VERSION 5.8 ;
BUSBITCHARS "[]" ;
DIVIDERCHAR "/" ;
UNITS
    DATABASE MICRONS 1000 ;
END UNITS

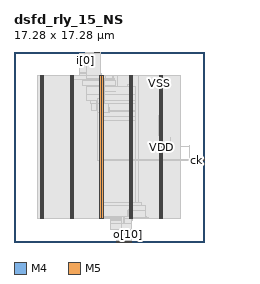
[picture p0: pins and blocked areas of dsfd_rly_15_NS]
MACRO dsfd_rly_15_NS
  FOREIGN dsfd_rly_15_NS 0 0 ;
  CLASS BLOCK ;
  SIZE 17.28 BY 17.28 ;
  PIN ck
    DIRECTION INPUT ;
    USE SIGNAL ;
    PORT
      LAYER M4 ;
        RECT  17.196 7.44 17.28 7.464 ;
    END
  END ck
  PIN i[0]
    DIRECTION INPUT ;
    USE SIGNAL ;
    PORT
      LAYER M5 ;
        RECT  6.48 17.196 6.504 17.28 ;
    END
  END i[0]
  PIN i[10]
    DIRECTION INPUT ;
    USE SIGNAL ;
    PORT
      LAYER M5 ;
        RECT  7.44 17.196 7.464 17.28 ;
    END
  END i[10]
  PIN i[11]
    DIRECTION INPUT ;
    USE SIGNAL ;
    PORT
      LAYER M5 ;
        RECT  7.536 17.196 7.56 17.28 ;
    END
  END i[11]
  PIN i[12]
    DIRECTION INPUT ;
    USE SIGNAL ;
    PORT
      LAYER M5 ;
        RECT  7.632 17.196 7.656 17.28 ;
    END
  END i[12]
  PIN i[13]
    DIRECTION INPUT ;
    USE SIGNAL ;
    PORT
      LAYER M5 ;
        RECT  7.728 17.196 7.752 17.28 ;
    END
  END i[13]
  PIN i[14]
    DIRECTION INPUT ;
    USE SIGNAL ;
    PORT
      LAYER M5 ;
        RECT  7.824 17.196 7.848 17.28 ;
    END
  END i[14]
  PIN i[1]
    DIRECTION INPUT ;
    USE SIGNAL ;
    PORT
      LAYER M5 ;
        RECT  6.576 17.196 6.6 17.28 ;
    END
  END i[1]
  PIN i[2]
    DIRECTION INPUT ;
    USE SIGNAL ;
    PORT
      LAYER M5 ;
        RECT  6.672 17.196 6.696 17.28 ;
    END
  END i[2]
  PIN i[3]
    DIRECTION INPUT ;
    USE SIGNAL ;
    PORT
      LAYER M5 ;
        RECT  6.768 17.196 6.792 17.28 ;
    END
  END i[3]
  PIN i[4]
    DIRECTION INPUT ;
    USE SIGNAL ;
    PORT
      LAYER M5 ;
        RECT  6.864 17.196 6.888 17.28 ;
    END
  END i[4]
  PIN i[5]
    DIRECTION INPUT ;
    USE SIGNAL ;
    PORT
      LAYER M5 ;
        RECT  6.96 17.196 6.984 17.28 ;
    END
  END i[5]
  PIN i[6]
    DIRECTION INPUT ;
    USE SIGNAL ;
    PORT
      LAYER M5 ;
        RECT  7.056 17.196 7.08 17.28 ;
    END
  END i[6]
  PIN i[7]
    DIRECTION INPUT ;
    USE SIGNAL ;
    PORT
      LAYER M5 ;
        RECT  7.152 17.196 7.176 17.28 ;
    END
  END i[7]
  PIN i[8]
    DIRECTION INPUT ;
    USE SIGNAL ;
    PORT
      LAYER M5 ;
        RECT  7.248 17.196 7.272 17.28 ;
    END
  END i[8]
  PIN i[9]
    DIRECTION INPUT ;
    USE SIGNAL ;
    PORT
      LAYER M5 ;
        RECT  7.344 17.196 7.368 17.28 ;
    END
  END i[9]
  PIN o[0]
    DIRECTION OUTPUT ;
    USE SIGNAL ;
    PORT
      LAYER M5 ;
        RECT  9.36 0 9.384 0.084 ;
    END
  END o[0]
  PIN o[10]
    DIRECTION OUTPUT ;
    USE SIGNAL ;
    PORT
      LAYER M5 ;
        RECT  10.32 0 10.344 0.084 ;
    END
  END o[10]
  PIN o[11]
    DIRECTION OUTPUT ;
    USE SIGNAL ;
    PORT
      LAYER M5 ;
        RECT  10.416 0 10.44 0.084 ;
    END
  END o[11]
  PIN o[12]
    DIRECTION OUTPUT ;
    USE SIGNAL ;
    PORT
      LAYER M5 ;
        RECT  10.512 0 10.536 0.084 ;
    END
  END o[12]
  PIN o[13]
    DIRECTION OUTPUT ;
    USE SIGNAL ;
    PORT
      LAYER M5 ;
        RECT  10.608 0 10.632 0.084 ;
    END
  END o[13]
  PIN o[14]
    DIRECTION OUTPUT ;
    USE SIGNAL ;
    PORT
      LAYER M5 ;
        RECT  10.704 0 10.728 0.084 ;
    END
  END o[14]
  PIN o[1]
    DIRECTION OUTPUT ;
    USE SIGNAL ;
    PORT
      LAYER M5 ;
        RECT  9.456 0 9.48 0.084 ;
    END
  END o[1]
  PIN o[2]
    DIRECTION OUTPUT ;
    USE SIGNAL ;
    PORT
      LAYER M5 ;
        RECT  9.552 0 9.576 0.084 ;
    END
  END o[2]
  PIN o[3]
    DIRECTION OUTPUT ;
    USE SIGNAL ;
    PORT
      LAYER M5 ;
        RECT  9.648 0 9.672 0.084 ;
    END
  END o[3]
  PIN o[4]
    DIRECTION OUTPUT ;
    USE SIGNAL ;
    PORT
      LAYER M5 ;
        RECT  9.744 0 9.768 0.084 ;
    END
  END o[4]
  PIN o[5]
    DIRECTION OUTPUT ;
    USE SIGNAL ;
    PORT
      LAYER M5 ;
        RECT  9.84 0 9.864 0.084 ;
    END
  END o[5]
  PIN o[6]
    DIRECTION OUTPUT ;
    USE SIGNAL ;
    PORT
      LAYER M5 ;
        RECT  9.936 0 9.96 0.084 ;
    END
  END o[6]
  PIN o[7]
    DIRECTION OUTPUT ;
    USE SIGNAL ;
    PORT
      LAYER M5 ;
        RECT  10.032 0 10.056 0.084 ;
    END
  END o[7]
  PIN o[8]
    DIRECTION OUTPUT ;
    USE SIGNAL ;
    PORT
      LAYER M5 ;
        RECT  10.128 0 10.152 0.084 ;
    END
  END o[8]
  PIN o[9]
    DIRECTION OUTPUT ;
    USE SIGNAL ;
    PORT
      LAYER M5 ;
        RECT  10.224 0 10.248 0.084 ;
    END
  END o[9]
  PIN rs
    DIRECTION INPUT ;
    USE SIGNAL ;
    PORT
      LAYER M4 ;
        RECT  17.196 7.536 17.28 7.56 ;
    END
  END rs
  PIN VDD
    DIRECTION INOUT ;
    USE POWER ;
    PORT
      LAYER M5 ;
        RECT  13.392 2.151 13.512 15.129 ;
        RECT  10.692 2.151 10.812 15.129 ;
        RECT  7.992 2.151 8.112 15.129 ;
        RECT  5.292 2.151 5.412 15.129 ;
        RECT  2.592 2.151 2.712 15.129 ;
    END
  END VDD
  PIN VSS
    DIRECTION INOUT ;
    USE GROUND ;
    PORT
      LAYER M5 ;
        RECT  13.2 2.137 13.32 15.143 ;
        RECT  10.5 2.137 10.62 15.143 ;
        RECT  7.8 2.137 7.92 15.143 ;
        RECT  5.1 2.137 5.22 15.143 ;
        RECT  2.4 2.137 2.52 15.143 ;
    END
  END VSS
  # OT_OBS_CLOSED layer=M5 d_um=1.536 added=2
  OBS
    LAYER RVTN ;
     RECT  2.16 2.16 15.12 2.295 ;
     RECT  2.16 2.565 15.12 2.835 ;
     RECT  2.16 3.105 15.12 3.375 ;
     RECT  2.16 3.645 15.12 3.915 ;
     RECT  2.16 4.185 15.12 4.455 ;
     RECT  2.16 4.725 15.12 4.995 ;
     RECT  2.16 5.265 15.12 5.535 ;
     RECT  2.16 5.805 15.12 6.075 ;
     RECT  2.16 6.345 15.12 6.615 ;
     RECT  2.16 6.885 15.12 7.155 ;
     RECT  2.16 7.425 15.12 7.695 ;
     RECT  2.16 7.965 15.12 8.235 ;
     RECT  2.16 8.505 15.12 8.775 ;
     RECT  2.16 9.045 15.12 9.315 ;
     RECT  2.16 9.585 15.12 9.855 ;
     RECT  2.16 10.125 15.12 10.395 ;
     RECT  2.16 10.665 15.12 10.935 ;
     RECT  2.16 11.205 15.12 11.475 ;
     RECT  2.16 11.745 15.12 12.015 ;
     RECT  2.16 12.285 15.12 12.555 ;
     RECT  2.16 12.825 15.12 13.095 ;
     RECT  2.16 13.365 15.12 13.635 ;
     RECT  2.16 13.905 15.12 14.175 ;
     RECT  2.16 14.445 15.12 14.715 ;
     RECT  2.16 14.985 15.12 15.12 ;
    LAYER RVTP ;
     RECT  2.16 2.295 15.12 2.565 ;
     RECT  2.16 2.835 15.12 3.105 ;
     RECT  2.16 3.375 15.12 3.645 ;
     RECT  2.16 3.915 15.12 4.185 ;
     RECT  2.16 4.455 15.12 4.725 ;
     RECT  2.16 4.995 15.12 5.265 ;
     RECT  2.16 5.535 15.12 5.805 ;
     RECT  2.16 6.075 15.12 6.345 ;
     RECT  2.16 6.615 15.12 6.885 ;
     RECT  2.16 7.155 15.12 7.425 ;
     RECT  2.16 7.695 15.12 7.965 ;
     RECT  2.16 8.235 15.12 8.505 ;
     RECT  2.16 8.775 15.12 9.045 ;
     RECT  2.16 9.315 15.12 9.585 ;
     RECT  2.16 9.855 15.12 10.125 ;
     RECT  2.16 10.395 15.12 10.665 ;
     RECT  2.16 10.935 15.12 11.205 ;
     RECT  2.16 11.475 15.12 11.745 ;
     RECT  2.16 12.015 15.12 12.285 ;
     RECT  2.16 12.555 15.12 12.825 ;
     RECT  2.16 13.095 15.12 13.365 ;
     RECT  2.16 13.635 15.12 13.905 ;
     RECT  2.16 14.175 15.12 14.445 ;
     RECT  2.16 14.715 15.12 14.985 ;
    LAYER M1 ;
     RECT  2.16 2.151 15.12 15.129 ;
    LAYER M2 ;
     RECT  2.16 2.151 8.311 15.129 ;
     RECT  8.311 2.106 9.427 15.129 ;
     RECT  9.427 2.034 10.751 15.129 ;
     RECT  10.751 2.106 11.291 15.129 ;
     RECT  11.291 2.151 15.12 15.129 ;
     RECT  15.12 8.712 15.971 8.73 ;
    LAYER M3 ;
     RECT  9.36 0.091 10.35 1.099 ;
     RECT  8.82 1.099 10.35 1.723 ;
     RECT  8.82 1.723 10.422 1.963 ;
     RECT  8.82 1.963 10.494 2.011 ;
     RECT  8.82 2.011 10.71 2.029 ;
     RECT  8.82 2.029 10.746 2.101 ;
     RECT  8.316 2.101 11.286 2.143 ;
     RECT  12.06 2.191 12.222 2.237 ;
     RECT  7.815 2.143 11.286 2.263 ;
     RECT  12.06 2.237 12.078 2.263 ;
     RECT  7.815 2.263 12.078 2.291 ;
     RECT  2.415 2.143 2.505 2.413 ;
     RECT  5.115 2.143 5.205 2.413 ;
     RECT  13.215 2.143 13.305 2.413 ;
     RECT  7.815 2.291 11.934 3.299 ;
     RECT  7.815 3.299 11.826 3.335 ;
     RECT  7.815 3.335 11.574 3.569 ;
     RECT  7.815 3.569 11.43 3.605 ;
     RECT  15.948 7.531 15.966 8.735 ;
     RECT  14.22 8.851 14.238 9.545 ;
     RECT  13.215 2.413 13.497 9.661 ;
     RECT  7.815 3.605 11.07 11.011 ;
     RECT  7.776 11.011 11.07 11.371 ;
     RECT  13.104 9.661 13.497 11.471 ;
     RECT  7.74 11.371 11.07 11.911 ;
     RECT  7.668 11.911 11.07 11.941 ;
     RECT  7.056 11.941 11.07 12.631 ;
     RECT  6.912 12.631 11.07 12.901 ;
     RECT  6.588 12.901 11.07 13.441 ;
     RECT  6.552 13.441 11.07 14.099 ;
     RECT  6.552 14.099 9.27 14.251 ;
     RECT  10.296 14.099 10.797 14.369 ;
     RECT  6.264 14.251 9.27 14.675 ;
     RECT  6.264 14.675 9.162 14.791 ;
     RECT  2.415 2.413 2.697 14.867 ;
     RECT  5.115 2.413 5.397 14.867 ;
     RECT  10.515 14.369 10.797 14.867 ;
     RECT  13.215 11.471 13.497 14.867 ;
     RECT  6.156 14.791 9.162 14.909 ;
     RECT  8.928 14.909 9.018 14.945 ;
     RECT  9 14.945 9.018 15.017 ;
     RECT  6.156 14.909 7.974 15.025 ;
     RECT  2.415 14.867 2.505 15.137 ;
     RECT  5.115 14.867 5.205 15.137 ;
     RECT  10.515 14.867 10.605 15.137 ;
     RECT  13.215 14.867 13.305 15.137 ;
     RECT  5.976 15.025 7.974 15.341 ;
     RECT  5.976 15.341 7.002 15.389 ;
     RECT  7.74 15.341 7.758 15.389 ;
     RECT  5.976 15.389 6.786 16.013 ;
     RECT  5.976 16.013 6.426 17.117 ;
     RECT  5.976 17.117 5.994 17.165 ;
    LAYER M4 ;
     RECT  2.408 2.148 2.512 15.132 ;
     RECT  2.512 2.418 2.704 14.862 ;
     RECT  5.108 2.148 5.212 15.132 ;
     RECT  5.212 2.418 5.404 14.862 ;
     RECT  5.965 17.136 6.397 17.16 ;
     RECT  6.397 17.088 6.515 17.16 ;
     RECT  5.404 14.832 6.649 14.856 ;
     RECT  6.649 14.832 6.661 15.096 ;
     RECT  6.661 14.832 6.757 15.384 ;
     RECT  6.757 14.832 6.899 16.008 ;
     RECT  6.515 17.088 7.091 17.112 ;
     RECT  7.045 11.952 7.477 11.976 ;
     RECT  7.477 11.952 7.621 12.792 ;
     RECT  6.899 14.832 7.805 15.384 ;
     RECT  7.621 7.44 7.808 7.464 ;
     RECT  7.621 11.952 7.808 13.08 ;
     RECT  7.805 14.832 7.808 15.336 ;
     RECT  7.808 2.148 7.912 15.336 ;
     RECT  7.912 2.418 7.985 15.336 ;
     RECT  7.985 2.418 8.104 14.862 ;
     RECT  8.104 11.76 8.243 13.704 ;
     RECT  8.243 11.76 8.627 12.552 ;
     RECT  8.627 11.76 8.668 12.264 ;
     RECT  8.668 12.24 8.705 12.264 ;
     RECT  8.104 14.832 8.957 14.856 ;
     RECT  8.243 13.68 9.245 13.704 ;
     RECT  8.809 1.104 9.491 1.128 ;
     RECT  9.349 0.096 9.541 0.12 ;
     RECT  9.541 0.096 9.683 0.648 ;
     RECT  9.493 1.68 9.817 1.704 ;
     RECT  9.817 1.68 9.971 2.28 ;
     RECT  9.971 1.728 10.357 2.28 ;
     RECT  9.683 0.096 10.361 0.216 ;
     RECT  10.357 1.728 10.477 2.904 ;
     RECT  10.477 1.968 10.508 2.904 ;
     RECT  8.104 7.44 10.508 7.464 ;
     RECT  10.361 0.192 10.547 0.216 ;
     RECT  10.508 1.968 10.612 15.132 ;
     RECT  10.612 1.968 10.739 14.862 ;
     RECT  10.739 2.208 10.804 14.862 ;
     RECT  10.804 2.208 11.945 2.904 ;
     RECT  11.945 2.208 12.233 2.232 ;
     RECT  10.804 7.44 13.208 7.464 ;
     RECT  13.208 2.148 13.312 15.132 ;
     RECT  13.312 2.418 13.504 14.862 ;
     RECT  13.504 7.44 15.937 7.464 ;
     RECT  15.937 7.44 17.244 7.56 ;
    LAYER M5 ;
     RECT  9.36 0.016 10.728 0.131 ;
     RECT  9.456 0.131 10.728 1.139 ;
     RECT  9.744 1.139 10.728 1.715 ;
     RECT  2.4 2.137 2.52 2.151 ;
     RECT  5.1 2.137 5.22 2.151 ;
     RECT  7.8 2.137 7.92 2.151 ;
     RECT  10.032 1.715 10.728 2.151 ;
     RECT  13.2 2.137 13.32 2.151 ;
     RECT  10.032 2.151 10.812 2.291 ;
     RECT  10.368 2.291 10.812 2.915 ;
     RECT  7.8 2.151 8.112 7.429 ;
     RECT  7.632 7.429 8.112 11.749 ;
     RECT  7.632 11.749 8.616 12.563 ;
     RECT  7.632 12.563 8.232 13.091 ;
     RECT  7.8 13.091 8.232 14.821 ;
     RECT  6.576 14.821 8.232 14.867 ;
     RECT  2.4 2.151 2.712 15.129 ;
     RECT  5.1 2.151 5.412 15.129 ;
     RECT  6.576 14.867 8.112 15.129 ;
     RECT  10.5 2.915 10.812 15.129 ;
     RECT  13.2 2.151 13.512 15.129 ;
     RECT  2.4 15.129 2.52 15.143 ;
     RECT  5.1 15.129 5.22 15.143 ;
     RECT  6.576 15.129 7.92 15.143 ;
     RECT  10.5 15.129 10.62 15.143 ;
     RECT  13.2 15.129 13.32 15.143 ;
     RECT  6.576 15.143 7.848 17.125 ;
     RECT  6.48 17.125 7.848 17.232 ;
     RECT  5.412 14.821 6.576 15.129 ;
     RECT  5.22 15.129 6.576 15.143 ;
  END
END dsfd_rly_15_NS
END LIBRARY
